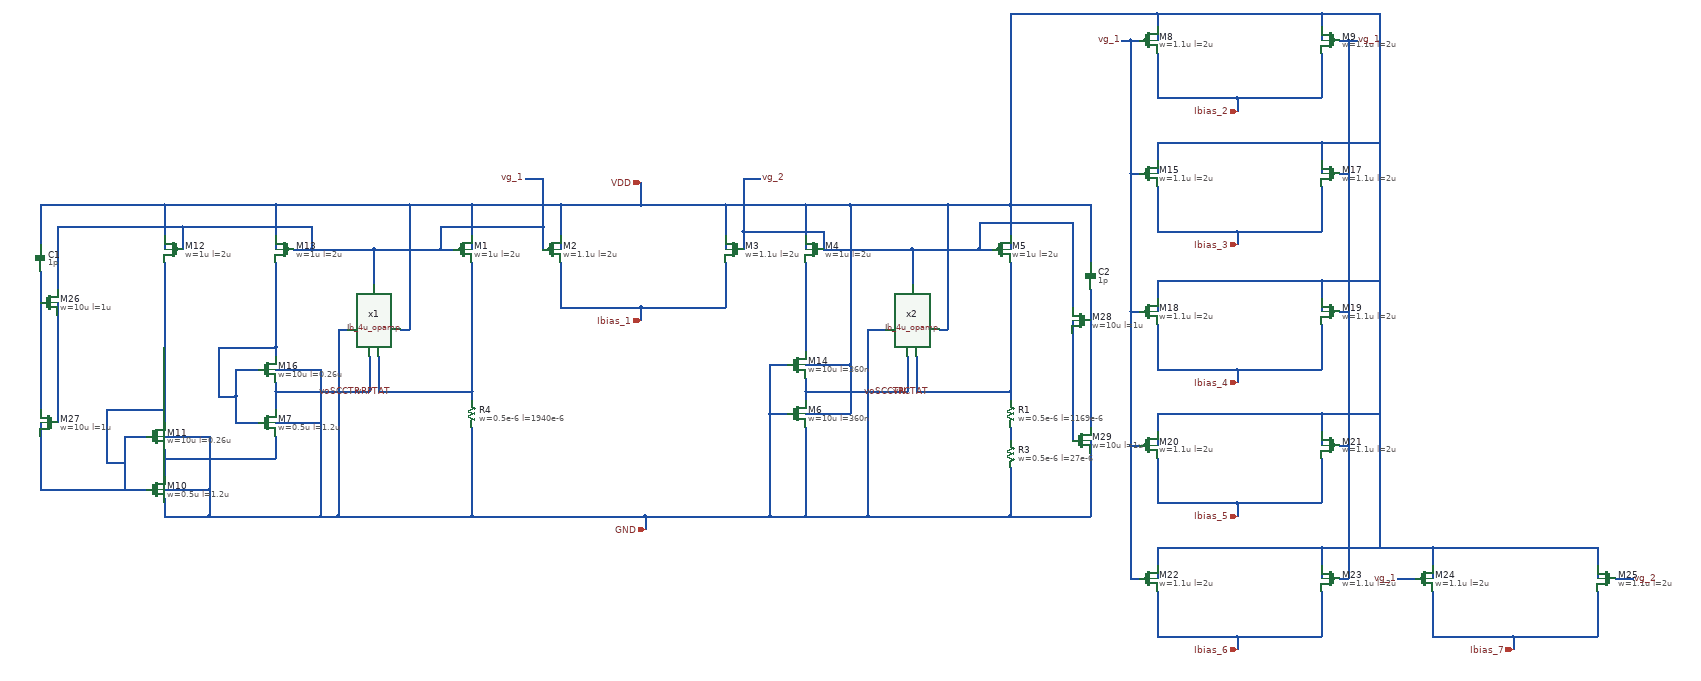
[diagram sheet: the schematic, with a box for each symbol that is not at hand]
v {xschem version=3.4.6 file_version=1.2}
G {}
K {}
V {}
S {}
E {}
N 1770 -1030 1770 -990 {lab=vg_2}
N 1650 -730 1690 -730 {lab=GND}
N 1650 -620 1690 -620 {lab=GND}
N 1730 -670 1730 -650 {lab=voSCCTN}
N 1970 -990 1970 -910 {lab=vg_2}
N 1770 -990 1970 -990 {lab=vg_2}
N 2120 -990 2150 -990 {lab=vg_2}
N 1180 -1090 1180 -990 {lab=VDD}
N 1550 -1090 1550 -990 {lab=VDD}
N 1730 -1090 1730 -990 {lab=VDD}
N 2190 -1090 2190 -990 {lab=VDD}
N 290 -1090 540 -1090 {lab=VDD}
N 980 -1090 980 -990 {lab=VDD}
N 840 -1090 980 -1090 {lab=VDD}
N 910 -990 940 -990 {lab=vg_1}
N 910 -1040 910 -990 {lab=vg_1}
N 1140 -1040 1140 -990 {lab=vg_1}
N 1590 -1030 1590 -990 {lab=vg_2}
N 760 -990 910 -990 {lab=vg_1}
N 540 -1090 540 -990 {lab=VDD}
N 760 -990 760 -910 {lab=vg_1}
N 620 -990 760 -990 {lab=vg_1}
N 820 -810 840 -810 {lab=VDD}
N 840 -1090 840 -810 {lab=VDD}
N 540 -1090 840 -1090 {lab=VDD}
N 540 -670 540 -630 {lab=voSCCTP}
N 540 -720 640 -720 {lab=GND}
N 640 -720 640 -600 {lab=GND}
N 540 -600 640 -600 {lab=GND}
N 450 -720 500 -720 {lab=#net1}
N 450 -660 450 -600 {lab=#net1}
N 450 -600 500 -600 {lab=#net1}
N 540 -770 540 -750 {lab=#net1}
N 410 -660 450 -660 {lab=#net1}
N 450 -720 450 -660 {lab=#net1}
N 410 -770 410 -660 {lab=#net1}
N 410 -770 540 -770 {lab=#net1}
N 540 -960 540 -770 {lab=#net1}
N 540 -670 750 -670 {lab=voSCCTP}
N 540 -690 540 -670 {lab=voSCCTP}
N 750 -750 750 -670 {lab=voSCCTP}
N 290 -520 290 -480 {lab=#net2}
N 290 -570 390 -570 {lab=GND}
N 390 -570 390 -450 {lab=GND}
N 290 -450 390 -450 {lab=GND}
N 200 -570 250 -570 {lab=#net3}
N 200 -510 200 -450 {lab=#net3}
N 200 -450 250 -450 {lab=#net3}
N 160 -510 200 -510 {lab=#net3}
N 200 -570 200 -510 {lab=#net3}
N 290 -520 540 -520 {lab=#net2}
N 290 -540 290 -520 {lab=#net2}
N 540 -570 540 -520 {lab=#net2}
N 290 -630 290 -600 {lab=#net3}
N 290 -1090 290 -990 {lab=VDD}
N 330 -1040 330 -990 {lab=vg_1}
N 330 -1040 620 -1040 {lab=vg_1}
N 620 -1040 620 -990 {lab=vg_1}
N 580 -990 620 -990 {lab=vg_1}
N 290 -430 290 -390 {lab=GND}
N 160 -630 160 -510 {lab=#net3}
N 160 -630 290 -630 {lab=#net3}
N 290 -960 290 -630 {lab=#net3}
N 1650 -730 1650 -620 {lab=GND}
N 1870 -390 2190 -390 {lab=GND}
N 640 -600 640 -390 {lab=GND}
N 390 -390 640 -390 {lab=GND}
N 390 -450 390 -390 {lab=GND}
N 290 -390 390 -390 {lab=GND}
N 1730 -620 1830 -620 {lab=VDD}
N 2050 -1090 2190 -1090 {lab=VDD}
N 980 -670 980 -650 {lab=vRPTAT}
N 980 -590 980 -390 {lab=GND}
N 680 -390 980 -390 {lab=GND}
N 770 -750 770 -670 {lab=vRPTAT}
N 770 -670 980 -670 {lab=vRPTAT}
N 980 -960 980 -670 {lab=vRPTAT}
N 2190 -670 2190 -650 {lab=vRCTAT}
N 1980 -670 2190 -670 {lab=vRCTAT}
N 2190 -960 2190 -670 {lab=vRCTAT}
N 1980 -750 1980 -670 {lab=vRCTAT}
N 1960 -750 1960 -670 {lab=voSCCTN}
N 1730 -960 1730 -760 {lab=#net4}
N 1730 -590 1730 -390 {lab=GND}
N 1730 -670 1960 -670 {lab=voSCCTN}
N 1730 -700 1730 -670 {lab=voSCCTN}
N 1830 -730 1830 -620 {lab=VDD}
N 1730 -1090 1830 -1090 {lab=VDD}
N 1870 -810 1910 -810 {lab=GND}
N 1870 -810 1870 -390 {lab=GND}
N 1730 -390 1870 -390 {lab=GND}
N 2030 -810 2050 -810 {lab=VDD}
N 2050 -1090 2050 -810 {lab=VDD}
N 1830 -1090 2050 -1090 {lab=VDD}
N 1650 -390 1730 -390 {lab=GND}
N 1650 -620 1650 -390 {lab=GND}
N 1590 -1030 1770 -1030 {lab=vg_2}
N 910 -1040 1140 -1040 {lab=vg_1}
N 980 -1090 1180 -1090 {lab=VDD}
N 1550 -1090 1730 -1090 {lab=VDD}
N 1360 -1090 1550 -1090 {lab=VDD}
N 680 -810 700 -810 {lab=GND}
N 680 -810 680 -390 {lab=GND}
N 640 -390 680 -390 {lab=GND}
N 1730 -730 1830 -730 {lab=VDD}
N 1830 -1090 1830 -730 {lab=VDD}
N 1360 -860 1550 -860 {lab=Ibias_1}
N 1180 -960 1180 -860 {lab=Ibias_1}
N 1550 -960 1550 -860 {lab=Ibias_1}
N 1360 -860 1360 -830 {lab=Ibias_1}
N 1180 -860 1360 -860 {lab=Ibias_1}
N 1360 -1140 1360 -1090 {lab=VDD}
N 1180 -1090 1360 -1090 {lab=VDD}
N 1370 -390 1650 -390 {lab=GND}
N 1370 -390 1370 -360 {lab=GND}
N 980 -390 1370 -390 {lab=GND}
N 2700 -1330 2890 -1330 {lab=Ibias_2}
N 2520 -1430 2520 -1330 {lab=Ibias_2}
N 2890 -1430 2890 -1330 {lab=Ibias_2}
N 2700 -1330 2700 -1300 {lab=Ibias_2}
N 2520 -1330 2700 -1330 {lab=Ibias_2}
N 2700 -1030 2890 -1030 {lab=Ibias_3}
N 2520 -1130 2520 -1030 {lab=Ibias_3}
N 2890 -1130 2890 -1030 {lab=Ibias_3}
N 2700 -1030 2700 -1000 {lab=Ibias_3}
N 2520 -1030 2700 -1030 {lab=Ibias_3}
N 2700 -720 2890 -720 {lab=Ibias_4}
N 2520 -820 2520 -720 {lab=Ibias_4}
N 2890 -820 2890 -720 {lab=Ibias_4}
N 2700 -720 2700 -690 {lab=Ibias_4}
N 2520 -720 2700 -720 {lab=Ibias_4}
N 2700 -420 2890 -420 {lab=Ibias_5}
N 2520 -520 2520 -420 {lab=Ibias_5}
N 2890 -520 2890 -420 {lab=Ibias_5}
N 2700 -420 2700 -390 {lab=Ibias_5}
N 2520 -420 2700 -420 {lab=Ibias_5}
N 2700 -120 2890 -120 {lab=Ibias_6}
N 2520 -220 2520 -120 {lab=Ibias_6}
N 2890 -220 2890 -120 {lab=Ibias_6}
N 2700 -120 2700 -90 {lab=Ibias_6}
N 2520 -120 2700 -120 {lab=Ibias_6}
N 3320 -120 3510 -120 {lab=Ibias_7}
N 3140 -220 3140 -120 {lab=Ibias_7}
N 3510 -220 3510 -120 {lab=Ibias_7}
N 3320 -120 3320 -90 {lab=Ibias_7}
N 3140 -120 3320 -120 {lab=Ibias_7}
N 2520 -620 2520 -550 {lab=VDD}
N 2520 -620 2890 -620 {lab=VDD}
N 2890 -620 2890 -550 {lab=VDD}
N 2520 -920 2520 -850 {lab=VDD}
N 2520 -920 2890 -920 {lab=VDD}
N 2890 -920 2890 -850 {lab=VDD}
N 2520 -1230 2520 -1160 {lab=VDD}
N 2520 -1230 2890 -1230 {lab=VDD}
N 2890 -1230 2890 -1160 {lab=VDD}
N 2520 -1520 2520 -1460 {lab=VDD}
N 2520 -1520 2890 -1520 {lab=VDD}
N 2890 -1520 2890 -1460 {lab=VDD}
N 2520 -320 2520 -250 {lab=VDD}
N 2520 -320 2890 -320 {lab=VDD}
N 2890 -320 2890 -250 {lab=VDD}
N 3140 -320 3140 -250 {lab=VDD}
N 3140 -320 3510 -320 {lab=VDD}
N 3510 -320 3510 -250 {lab=VDD}
N 3020 -320 3140 -320 {lab=VDD}
N 2890 -620 3020 -620 {lab=VDD}
N 3020 -620 3020 -320 {lab=VDD}
N 2890 -320 3020 -320 {lab=VDD}
N 3020 -920 3020 -620 {lab=VDD}
N 2890 -920 3020 -920 {lab=VDD}
N 3020 -1230 3020 -920 {lab=VDD}
N 2890 -1230 3020 -1230 {lab=VDD}
N 3020 -1520 3020 -1230 {lab=VDD}
N 2890 -1520 3020 -1520 {lab=VDD}
N 2190 -1520 2190 -1090 {lab=VDD}
N 2190 -1520 2520 -1520 {lab=VDD}
N 1140 -1150 1140 -1040 {lab=vg_1}
N 1100 -1150 1140 -1150 {lab=vg_1}
N 1590 -1150 1630 -1150 {lab=vg_2}
N 1590 -1150 1590 -1030 {lab=vg_2}
N 2460 -1460 2480 -1460 {lab=vg_1}
N 2460 -550 2460 -250 {lab=vg_1}
N 2440 -1460 2460 -1460 {lab=vg_1}
N 2460 -250 2480 -250 {lab=vg_1}
N 2460 -550 2480 -550 {lab=vg_1}
N 2460 -850 2460 -550 {lab=vg_1}
N 2460 -850 2480 -850 {lab=vg_1}
N 2460 -1160 2460 -850 {lab=vg_1}
N 2460 -1160 2480 -1160 {lab=vg_1}
N 2460 -1460 2460 -1160 {lab=vg_1}
N 2930 -1460 2950 -1460 {lab=vg_1}
N 2950 -1460 2970 -1460 {lab=vg_1}
N 2950 -1460 2950 -1160 {lab=vg_1}
N 2930 -1160 2950 -1160 {lab=vg_1}
N 2950 -850 2950 -550 {lab=vg_1}
N 2930 -550 2950 -550 {lab=vg_1}
N 2930 -850 2950 -850 {lab=vg_1}
N 2950 -1160 2950 -850 {lab=vg_1}
N 2950 -550 2950 -250 {lab=vg_1}
N 2930 -250 2950 -250 {lab=vg_1}
N 3060 -250 3100 -250 {lab=vg_1}
N 3550 -250 3590 -250 {lab=vg_2}
N 2190 -590 2190 -560 {lab=#net5}
N 2190 -500 2190 -390 {lab=GND}
N 10 -600 10 -450 {lab=#net3}
N 10 -450 200 -450 {lab=#net3}
N 10 -940 10 -630 {lab=#net6}
N 10 -1090 290 -1090 {lab=VDD}
N 10 -1090 10 -1000 {lab=VDD}
N 50 -1040 50 -900 {lab=vg_1}
N 50 -1040 330 -1040 {lab=vg_1}
N 50 -870 50 -600 {lab=#net7}
N 2370 -560 2370 -390 {lab=GND}
N 2370 -900 2370 -590 {lab=#net8}
N 2330 -830 2330 -560 {lab=#net9}
N 2190 -390 2370 -390 {lab=GND}
N 2370 -1090 2370 -960 {lab=VDD}
N 2190 -1090 2370 -1090 {lab=VDD}
N 2330 -1050 2330 -860 {lab=vg_2}
N 2120 -1050 2330 -1050 {lab=vg_2}
N 2120 -1050 2120 -990 {lab=vg_2}
N 1970 -990 2120 -990 {lab=vg_2}
C {iopin.sym} 1360 -1140 0 0 {name=p1 lab=VDD}
C {iopin.sym} 1370 -360 0 0 {name=p2 lab=GND}
C {iopin.sym} 1360 -830 0 0 {name=p3 lab=Ibias_1}
C {lab_pin.sym} 730 -670 3 0 {name=p9 sig_type=std_logic lab=voSCCTP}
C {lab_pin.sym} 1960 -670 3 0 {name=p10 sig_type=std_logic lab=voSCCTN}
C {lab_pin.sym} 2010 -670 3 0 {name=p11 sig_type=std_logic lab=vRCTAT}
C {lab_pin.sym} 800 -670 3 0 {name=p12 sig_type=std_logic lab=vRPTAT}
C {sg13g2_pr/sg13_lv_pmos.sym} 960 -990 0 0 {name=M1
l=2u
w=1u
ng=1
m=1
model=sg13_lv_pmos
spiceprefix=X
}
C {sg13g2_pr/sg13_lv_pmos.sym} 1160 -990 0 0 {name=M2
l=2u
w=1.1u
ng=1
m=6
model=sg13_lv_pmos
spiceprefix=X
}
C {sg13g2_pr/sg13_lv_pmos.sym} 1570 -990 0 1 {name=M3
l=2u
w=1.1u
ng=1
m=6
model=sg13_lv_pmos
spiceprefix=X
}
C {sg13g2_pr/sg13_lv_pmos.sym} 1750 -990 0 1 {name=M4
l=2u
w=1u
ng=1
m=1
model=sg13_lv_pmos
spiceprefix=X
}
C {sg13g2_pr/sg13_lv_pmos.sym} 310 -990 0 1 {name=M12
l=2u
w=1u
ng=1
m=1
model=sg13_lv_pmos
spiceprefix=X
}
C {sg13g2_pr/sg13_lv_pmos.sym} 560 -990 0 1 {name=M13
l=2u
w=1u
ng=1
m=1
model=sg13_lv_pmos
spiceprefix=X
}
C {sg13g2_pr/sg13_lv_pmos.sym} 2170 -990 0 0 {name=M5
l=2u
w=1u
ng=1
m=1
model=sg13_lv_pmos
spiceprefix=X
}
C {sg13g2_pr/sg13_lv_nmos.sym} 520 -600 0 0 {name=M7
l=1.2u
w=0.5u
ng=1
m=1
model=sg13_lv_nmos
spiceprefix=X
}
C {sg13g2_pr/sg13_lv_nmos.sym} 270 -450 0 0 {name=M10
l=1.2u
w=0.5u
ng=1
m=1
model=sg13_lv_nmos
spiceprefix=X
}
C {sg13g2_pr/sg13_lv_nmos.sym} 270 -570 0 0 {name=M11
l=0.26u
w=10u
ng=1
m=30
model=sg13_lv_nmos
spiceprefix=X
}
C {sg13g2_pr/sg13_lv_nmos.sym} 520 -720 0 0 {name=M16
l=0.26u
w=10u
ng=1
m=30
model=sg13_lv_nmos
spiceprefix=X
}
C {sg13g2_pr/sg13_lv_pmos.sym} 1710 -620 0 0 {name=M6
l=360n
w=10u
ng=1
m=20
model=sg13_lv_pmos
spiceprefix=X
}
C {sg13g2_pr/sg13_lv_pmos.sym} 1710 -730 0 0 {name=M14
l=360n
w=10u
ng=1
m=1
model=sg13_lv_pmos
spiceprefix=X
}
C {iopin.sym} 2700 -1300 0 0 {name=p4 lab=Ibias_2}
C {sg13g2_pr/sg13_lv_pmos.sym} 2500 -1460 0 0 {name=M8
l=2u
w=1.1u
ng=1
m=6
model=sg13_lv_pmos
spiceprefix=X
}
C {sg13g2_pr/sg13_lv_pmos.sym} 2910 -1460 0 1 {name=M9
l=2u
w=1.1u
ng=1
m=6
model=sg13_lv_pmos
spiceprefix=X
}
C {iopin.sym} 2700 -1000 0 0 {name=p5 lab=Ibias_3}
C {sg13g2_pr/sg13_lv_pmos.sym} 2500 -1160 0 0 {name=M15
l=2u
w=1.1u
ng=1
m=6
model=sg13_lv_pmos
spiceprefix=X
}
C {sg13g2_pr/sg13_lv_pmos.sym} 2910 -1160 0 1 {name=M17
l=2u
w=1.1u
ng=1
m=6
model=sg13_lv_pmos
spiceprefix=X
}
C {iopin.sym} 2700 -690 0 0 {name=p6 lab=Ibias_4}
C {sg13g2_pr/sg13_lv_pmos.sym} 2500 -850 0 0 {name=M18
l=2u
w=1.1u
ng=1
m=6
model=sg13_lv_pmos
spiceprefix=X
}
C {sg13g2_pr/sg13_lv_pmos.sym} 2910 -850 0 1 {name=M19
l=2u
w=1.1u
ng=1
m=6
model=sg13_lv_pmos
spiceprefix=X
}
C {iopin.sym} 2700 -390 0 0 {name=p7 lab=Ibias_5}
C {sg13g2_pr/sg13_lv_pmos.sym} 2500 -550 0 0 {name=M20
l=2u
w=1.1u
ng=1
m=6
model=sg13_lv_pmos
spiceprefix=X
}
C {sg13g2_pr/sg13_lv_pmos.sym} 2910 -550 0 1 {name=M21
l=2u
w=1.1u
ng=1
m=6
model=sg13_lv_pmos
spiceprefix=X
}
C {iopin.sym} 2700 -90 0 0 {name=p8 lab=Ibias_6}
C {sg13g2_pr/sg13_lv_pmos.sym} 2500 -250 0 0 {name=M22
l=2u
w=1.1u
ng=1
m=6
model=sg13_lv_pmos
spiceprefix=X
}
C {sg13g2_pr/sg13_lv_pmos.sym} 2910 -250 0 1 {name=M23
l=2u
w=1.1u
ng=1
m=6
model=sg13_lv_pmos
spiceprefix=X
}
C {iopin.sym} 3320 -90 0 0 {name=p13 lab=Ibias_7}
C {sg13g2_pr/sg13_lv_pmos.sym} 3120 -250 0 0 {name=M24
l=2u
w=1.1u
ng=1
m=6
model=sg13_lv_pmos
spiceprefix=X
}
C {sg13g2_pr/sg13_lv_pmos.sym} 3530 -250 0 1 {name=M25
l=2u
w=1.1u
ng=1
m=6
model=sg13_lv_pmos
spiceprefix=X
}
C {lab_pin.sym} 1100 -1150 0 0 {name=p14 sig_type=std_logic lab=vg_1}
C {lab_pin.sym} 1630 -1150 0 1 {name=p15 sig_type=std_logic lab=vg_2}
C {lab_pin.sym} 2440 -1460 0 0 {name=p16 sig_type=std_logic lab=vg_1}
C {lab_pin.sym} 2970 -1460 0 1 {name=p17 sig_type=std_logic lab=vg_1}
C {lab_pin.sym} 3060 -250 0 0 {name=p18 sig_type=std_logic lab=vg_1}
C {lab_pin.sym} 3590 -250 0 1 {name=p19 sig_type=std_logic lab=vg_2}
C {sg13g2_pr/rppd.sym} 980 -620 0 0 {name=R4
w=0.5e-6
l=1940e-6
model=rppd
body=GND
spiceprefix=X
b=0
m=1
}
C {/shared/designs/SSDOR_w_startup_1V_ihp/Ib_4u/Ib_4u_opamp/Ib_4u_opamp.sym} 700 -750 1 1 {name=x1}
C {/shared/designs/SSDOR_w_startup_1V_ihp/Ib_4u/Ib_4u_opamp/Ib_4u_opamp.sym} 1910 -750 1 1 {name=x2}
C {sg13g2_pr/rppd.sym} 2190 -620 0 0 {name=R1
w=0.5e-6
l=1169e-6
model=rppd
body=GND
spiceprefix=X
b=0
m=1
}
C {sg13g2_pr/rhigh.sym} 2190 -530 0 0 {name=R3
w=0.5e-6
l=27e-6
model=rhigh
body=GND
spiceprefix=X
b=0
m=1
}
C {sg13g2_pr/sg13_lv_nmos.sym} 30 -870 0 0 {name=M26
l=1u
w=10u
ng=1
m=1
model=sg13_lv_nmos
spiceprefix=X
}
C {sg13g2_pr/sg13_lv_nmos.sym} 30 -600 0 1 {name=M27
l=1u
w=10u
ng=1
m=1
model=sg13_lv_nmos
spiceprefix=X
}
C {capa.sym} 10 -970 0 0 {name=C1
m=1
value=1p
footprint=1206
device="ceramic capacitor"}
C {sg13g2_pr/sg13_lv_nmos.sym} 2350 -830 0 1 {name=M28
l=1u
w=10u
ng=1
m=1
model=sg13_lv_nmos
spiceprefix=X
}
C {sg13g2_pr/sg13_lv_nmos.sym} 2350 -560 0 0 {name=M29
l=1u
w=10u
ng=1
m=1
model=sg13_lv_nmos
spiceprefix=X
}
C {capa.sym} 2370 -930 0 1 {name=C2
m=1
value=1p
footprint=1206
device="ceramic capacitor"}
